VERSION 5.7 ;
  NOWIREEXTENSIONATPIN ON ;
  DIVIDERCHAR "/" ;
  BUSBITCHARS "[]" ;
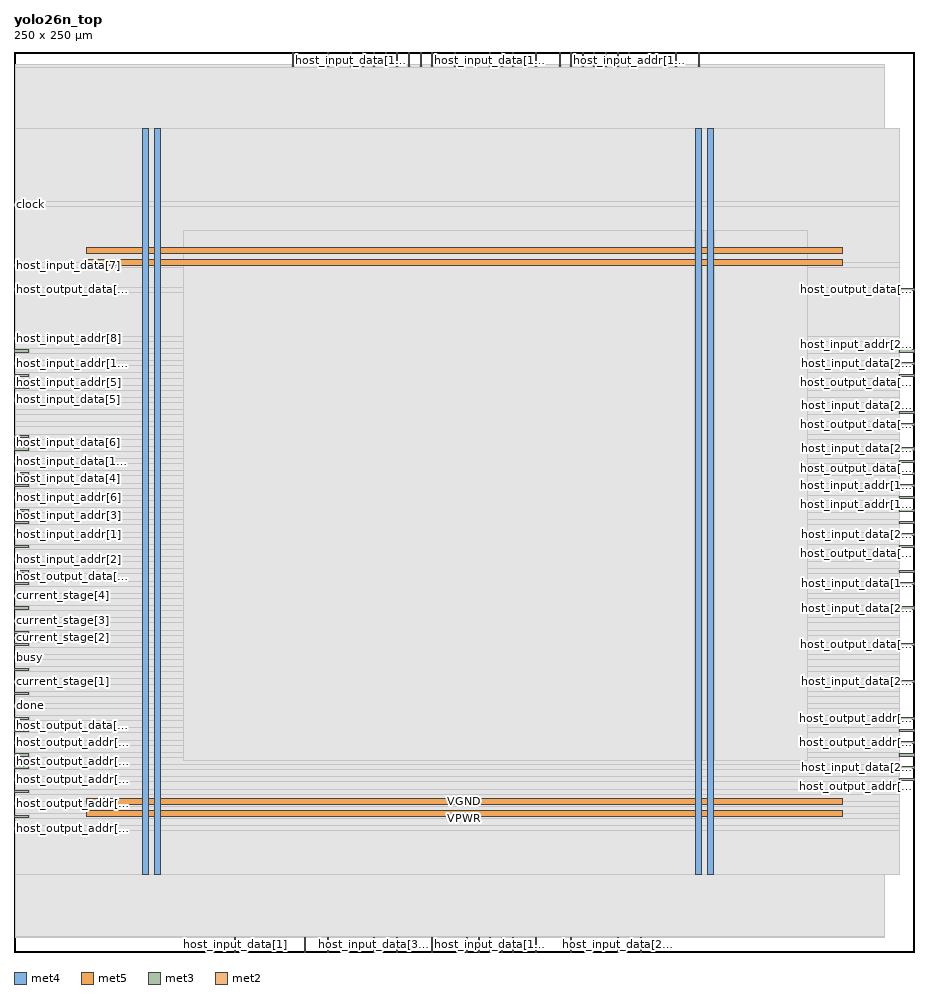
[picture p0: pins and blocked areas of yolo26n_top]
MACRO yolo26n_top
  CLASS BLOCK ;
  FOREIGN yolo26n_top ;
  ORIGIN 0.000 0.000 ;
  SIZE 250.000 BY 250.000 ;
  PIN VGND
    DIRECTION INOUT ;
    USE GROUND ;
    PORT
      LAYER met4 ;
        RECT 39.060 21.520 40.660 228.720 ;
    END
    PORT
      LAYER met4 ;
        RECT 192.660 21.520 194.260 228.720 ;
    END
    PORT
      LAYER met5 ;
        RECT 20.000 40.910 230.240 42.510 ;
    END
    PORT
      LAYER met5 ;
        RECT 20.000 194.090 230.240 195.690 ;
    END
  END VGND
  PIN VPWR
    DIRECTION INOUT ;
    USE POWER ;
    PORT
      LAYER met4 ;
        RECT 35.760 21.520 37.360 228.720 ;
    END
    PORT
      LAYER met4 ;
        RECT 189.360 21.520 190.960 228.720 ;
    END
    PORT
      LAYER met5 ;
        RECT 20.000 37.610 230.240 39.210 ;
    END
    PORT
      LAYER met5 ;
        RECT 20.000 190.790 230.240 192.390 ;
    END
  END VPWR
  PIN busy
    DIRECTION OUTPUT ;
    USE SIGNAL ;
    ANTENNADIFFAREA 0.795200 ;
    PORT
      LAYER met3 ;
        RECT 0.000 81.640 4.000 82.240 ;
    END
  END busy
  PIN clock
    DIRECTION INPUT ;
    USE SIGNAL ;
    ANTENNAGATEAREA 0.852000 ;
    PORT
      LAYER met3 ;
        RECT 0.000 207.440 4.000 208.040 ;
    END
  END clock
  PIN current_stage[0]
    DIRECTION OUTPUT ;
    USE SIGNAL ;
    ANTENNADIFFAREA 0.795200 ;
    PORT
      LAYER met3 ;
        RECT 0.000 71.440 4.000 72.040 ;
    END
  END current_stage[0]
  PIN current_stage[1]
    DIRECTION OUTPUT ;
    USE SIGNAL ;
    ANTENNADIFFAREA 0.795200 ;
    PORT
      LAYER met3 ;
        RECT 0.000 74.840 4.000 75.440 ;
    END
  END current_stage[1]
  PIN current_stage[2]
    DIRECTION OUTPUT ;
    USE SIGNAL ;
    ANTENNADIFFAREA 0.795200 ;
    PORT
      LAYER met3 ;
        RECT 0.000 85.040 4.000 85.640 ;
    END
  END current_stage[2]
  PIN current_stage[3]
    DIRECTION OUTPUT ;
    USE SIGNAL ;
    ANTENNADIFFAREA 0.795200 ;
    PORT
      LAYER met3 ;
        RECT 0.000 91.840 4.000 92.440 ;
    END
  END current_stage[3]
  PIN current_stage[4]
    DIRECTION OUTPUT ;
    USE SIGNAL ;
    ANTENNADIFFAREA 0.795200 ;
    PORT
      LAYER met3 ;
        RECT 0.000 98.640 4.000 99.240 ;
    END
  END current_stage[4]
  PIN done
    DIRECTION OUTPUT ;
    USE SIGNAL ;
    ANTENNADIFFAREA 0.795200 ;
    PORT
      LAYER met3 ;
        RECT 0.000 68.040 4.000 68.640 ;
    END
  END done
  PIN host_input_addr[0]
    DIRECTION INPUT ;
    USE SIGNAL ;
    ANTENNAGATEAREA 0.213000 ;
    PORT
      LAYER met3 ;
        RECT 0.000 112.240 4.000 112.840 ;
    END
  END host_input_addr[0]
  PIN host_input_addr[10]
    DIRECTION INPUT ;
    USE SIGNAL ;
    ANTENNAGATEAREA 0.196500 ;
    PORT
      LAYER met3 ;
        RECT 0.000 163.240 4.000 163.840 ;
    END
  END host_input_addr[10]
  PIN host_input_addr[11]
    DIRECTION INPUT ;
    USE SIGNAL ;
    ANTENNAGATEAREA 0.196500 ;
    PORT
      LAYER met2 ;
        RECT 135.330 246.000 135.610 250.000 ;
    END
  END host_input_addr[11]
  PIN host_input_addr[12]
    DIRECTION INPUT ;
    USE SIGNAL ;
    ANTENNAGATEAREA 0.196500 ;
    PORT
      LAYER met2 ;
        RECT 122.450 246.000 122.730 250.000 ;
    END
  END host_input_addr[12]
  PIN host_input_addr[13]
    DIRECTION INPUT ;
    USE SIGNAL ;
    ANTENNAGATEAREA 0.196500 ;
    PORT
      LAYER met3 ;
        RECT 246.000 122.440 250.000 123.040 ;
    END
  END host_input_addr[13]
  PIN host_input_addr[14]
    DIRECTION INPUT ;
    USE SIGNAL ;
    ANTENNAGATEAREA 0.196500 ;
    PORT
      LAYER met2 ;
        RECT 106.350 246.000 106.630 250.000 ;
    END
  END host_input_addr[14]
  PIN host_input_addr[15]
    DIRECTION INPUT ;
    USE SIGNAL ;
    ANTENNAGATEAREA 0.196500 ;
    PORT
      LAYER met3 ;
        RECT 246.000 129.240 250.000 129.840 ;
    END
  END host_input_addr[15]
  PIN host_input_addr[16]
    DIRECTION INPUT ;
    USE SIGNAL ;
    ANTENNAGATEAREA 0.196500 ;
    PORT
      LAYER met3 ;
        RECT 246.000 132.640 250.000 133.240 ;
    END
  END host_input_addr[16]
  PIN host_input_addr[17]
    DIRECTION INPUT ;
    USE SIGNAL ;
    ANTENNAGATEAREA 0.196500 ;
    PORT
      LAYER met2 ;
        RECT 161.090 246.000 161.370 250.000 ;
    END
  END host_input_addr[17]
  PIN host_input_addr[18]
    DIRECTION INPUT ;
    USE SIGNAL ;
    ANTENNAGATEAREA 0.196500 ;
    PORT
      LAYER met3 ;
        RECT 246.000 125.840 250.000 126.440 ;
    END
  END host_input_addr[18]
  PIN host_input_addr[19]
    DIRECTION INPUT ;
    USE SIGNAL ;
    ANTENNAGATEAREA 0.196500 ;
    PORT
      LAYER met2 ;
        RECT 170.750 246.000 171.030 250.000 ;
    END
  END host_input_addr[19]
  PIN host_input_addr[1]
    DIRECTION INPUT ;
    USE SIGNAL ;
    ANTENNAGATEAREA 0.196500 ;
    PORT
      LAYER met3 ;
        RECT 0.000 115.640 4.000 116.240 ;
    END
  END host_input_addr[1]
  PIN host_input_addr[20]
    DIRECTION INPUT ;
    USE SIGNAL ;
    ANTENNAGATEAREA 0.196500 ;
    PORT
      LAYER met3 ;
        RECT 246.000 166.640 250.000 167.240 ;
    END
  END host_input_addr[20]
  PIN host_input_addr[2]
    DIRECTION INPUT ;
    USE SIGNAL ;
    ANTENNAGATEAREA 0.196500 ;
    PORT
      LAYER met3 ;
        RECT 0.000 108.840 4.000 109.440 ;
    END
  END host_input_addr[2]
  PIN host_input_addr[3]
    DIRECTION INPUT ;
    USE SIGNAL ;
    ANTENNAGATEAREA 0.196500 ;
    PORT
      LAYER met3 ;
        RECT 0.000 119.040 4.000 119.640 ;
    END
  END host_input_addr[3]
  PIN host_input_addr[4]
    DIRECTION INPUT ;
    USE SIGNAL ;
    ANTENNAGATEAREA 0.196500 ;
    PORT
      LAYER met3 ;
        RECT 0.000 122.440 4.000 123.040 ;
    END
  END host_input_addr[4]
  PIN host_input_addr[5]
    DIRECTION INPUT ;
    USE SIGNAL ;
    ANTENNAGATEAREA 0.196500 ;
    PORT
      LAYER met3 ;
        RECT 0.000 159.840 4.000 160.440 ;
    END
  END host_input_addr[5]
  PIN host_input_addr[6]
    DIRECTION INPUT ;
    USE SIGNAL ;
    ANTENNAGATEAREA 0.196500 ;
    PORT
      LAYER met3 ;
        RECT 0.000 125.840 4.000 126.440 ;
    END
  END host_input_addr[6]
  PIN host_input_addr[7]
    DIRECTION INPUT ;
    USE SIGNAL ;
    ANTENNAGATEAREA 0.196500 ;
    PORT
      LAYER met3 ;
        RECT 0.000 166.640 4.000 167.240 ;
    END
  END host_input_addr[7]
  PIN host_input_addr[8]
    DIRECTION INPUT ;
    USE SIGNAL ;
    ANTENNAGATEAREA 0.196500 ;
    PORT
      LAYER met3 ;
        RECT 0.000 170.040 4.000 170.640 ;
    END
  END host_input_addr[8]
  PIN host_input_addr[9]
    DIRECTION INPUT ;
    USE SIGNAL ;
    ANTENNAGATEAREA 0.196500 ;
    PORT
      LAYER met2 ;
        RECT 109.570 246.000 109.850 250.000 ;
    END
  END host_input_addr[9]
  PIN host_input_data[0]
    DIRECTION INPUT ;
    USE SIGNAL ;
    ANTENNAGATEAREA 0.159000 ;
    PORT
      LAYER met2 ;
        RECT 80.590 0.000 80.870 4.000 ;
    END
  END host_input_data[0]
  PIN host_input_data[10]
    DIRECTION INPUT ;
    USE SIGNAL ;
    ANTENNAGATEAREA 0.159000 ;
    PORT
      LAYER met2 ;
        RECT 93.470 246.000 93.750 250.000 ;
    END
  END host_input_data[10]
  PIN host_input_data[11]
    DIRECTION INPUT ;
    USE SIGNAL ;
    ANTENNAGATEAREA 0.159000 ;
    PORT
      LAYER met2 ;
        RECT 151.430 246.000 151.710 250.000 ;
    END
  END host_input_data[11]
  PIN host_input_data[12]
    DIRECTION INPUT ;
    USE SIGNAL ;
    ANTENNAGATEAREA 0.213000 ;
    PORT
      LAYER met2 ;
        RECT 132.110 246.000 132.390 250.000 ;
    END
  END host_input_data[12]
  PIN host_input_data[13]
    DIRECTION INPUT ;
    USE SIGNAL ;
    ANTENNAGATEAREA 0.159000 ;
    PORT
      LAYER met3 ;
        RECT 0.000 136.040 4.000 136.640 ;
    END
  END host_input_data[13]
  PIN host_input_data[14]
    DIRECTION INPUT ;
    USE SIGNAL ;
    ANTENNAGATEAREA 0.159000 ;
    PORT
      LAYER met2 ;
        RECT 99.910 246.000 100.190 250.000 ;
    END
  END host_input_data[14]
  PIN host_input_data[15]
    DIRECTION INPUT ;
    USE SIGNAL ;
    ANTENNAGATEAREA 0.159000 ;
    PORT
      LAYER met2 ;
        RECT 132.110 0.000 132.390 4.000 ;
    END
  END host_input_data[15]
  PIN host_input_data[16]
    DIRECTION INPUT ;
    USE SIGNAL ;
    ANTENNAGATEAREA 0.159000 ;
    PORT
      LAYER met2 ;
        RECT 154.650 246.000 154.930 250.000 ;
    END
  END host_input_data[16]
  PIN host_input_data[17]
    DIRECTION INPUT ;
    USE SIGNAL ;
    ANTENNAGATEAREA 0.213000 ;
    PORT
      LAYER met2 ;
        RECT 157.870 246.000 158.150 250.000 ;
    END
  END host_input_data[17]
  PIN host_input_data[18]
    DIRECTION INPUT ;
    USE SIGNAL ;
    ANTENNAGATEAREA 0.213000 ;
    PORT
      LAYER met3 ;
        RECT 246.000 102.040 250.000 102.640 ;
    END
  END host_input_data[18]
  PIN host_input_data[19]
    DIRECTION INPUT ;
    USE SIGNAL ;
    ANTENNAGATEAREA 0.159000 ;
    PORT
      LAYER met2 ;
        RECT 190.070 246.000 190.350 250.000 ;
    END
  END host_input_data[19]
  PIN host_input_data[1]
    DIRECTION INPUT ;
    USE SIGNAL ;
    ANTENNAGATEAREA 0.159000 ;
    PORT
      LAYER met2 ;
        RECT 61.270 0.000 61.550 4.000 ;
    END
  END host_input_data[1]
  PIN host_input_data[20]
    DIRECTION INPUT ;
    USE SIGNAL ;
    ANTENNAGATEAREA 0.159000 ;
    PORT
      LAYER met3 ;
        RECT 246.000 163.240 250.000 163.840 ;
    END
  END host_input_data[20]
  PIN host_input_data[21]
    DIRECTION INPUT ;
    USE SIGNAL ;
    ANTENNAGATEAREA 0.213000 ;
    PORT
      LAYER met3 ;
        RECT 246.000 149.640 250.000 150.240 ;
    END
  END host_input_data[21]
  PIN host_input_data[22]
    DIRECTION INPUT ;
    USE SIGNAL ;
    ANTENNAGATEAREA 0.159000 ;
    PORT
      LAYER met3 ;
        RECT 246.000 115.640 250.000 116.240 ;
    END
  END host_input_data[22]
  PIN host_input_data[23]
    DIRECTION INPUT ;
    USE SIGNAL ;
    ANTENNAGATEAREA 0.213000 ;
    PORT
      LAYER met3 ;
        RECT 246.000 139.440 250.000 140.040 ;
    END
  END host_input_data[23]
  PIN host_input_data[24]
    DIRECTION INPUT ;
    USE SIGNAL ;
    ANTENNAGATEAREA 0.213000 ;
    PORT
      LAYER met2 ;
        RECT 167.530 0.000 167.810 4.000 ;
    END
  END host_input_data[24]
  PIN host_input_data[25]
    DIRECTION INPUT ;
    USE SIGNAL ;
    ANTENNAGATEAREA 0.159000 ;
    PORT
      LAYER met3 ;
        RECT 246.000 51.040 250.000 51.640 ;
    END
  END host_input_data[25]
  PIN host_input_data[26]
    DIRECTION INPUT ;
    USE SIGNAL ;
    ANTENNAGATEAREA 0.213000 ;
    PORT
      LAYER met3 ;
        RECT 246.000 74.840 250.000 75.440 ;
    END
  END host_input_data[26]
  PIN host_input_data[27]
    DIRECTION INPUT ;
    USE SIGNAL ;
    ANTENNAGATEAREA 0.213000 ;
    PORT
      LAYER met3 ;
        RECT 246.000 95.240 250.000 95.840 ;
    END
  END host_input_data[27]
  PIN host_input_data[28]
    DIRECTION INPUT ;
    USE SIGNAL ;
    ANTENNAGATEAREA 0.159000 ;
    PORT
      LAYER met2 ;
        RECT 144.990 0.000 145.270 4.000 ;
    END
  END host_input_data[28]
  PIN host_input_data[29]
    DIRECTION INPUT ;
    USE SIGNAL ;
    ANTENNAGATEAREA 0.159000 ;
    PORT
      LAYER met2 ;
        RECT 135.330 0.000 135.610 4.000 ;
    END
  END host_input_data[29]
  PIN host_input_data[2]
    DIRECTION INPUT ;
    USE SIGNAL ;
    ANTENNAGATEAREA 0.159000 ;
    PORT
      LAYER met3 ;
        RECT 0.000 78.240 4.000 78.840 ;
    END
  END host_input_data[2]
  PIN host_input_data[30]
    DIRECTION INPUT ;
    USE SIGNAL ;
    ANTENNAGATEAREA 0.159000 ;
    PORT
      LAYER met2 ;
        RECT 116.010 0.000 116.290 4.000 ;
    END
  END host_input_data[30]
  PIN host_input_data[31]
    DIRECTION INPUT ;
    USE SIGNAL ;
    ANTENNAGATEAREA 0.159000 ;
    PORT
      LAYER met2 ;
        RECT 99.910 0.000 100.190 4.000 ;
    END
  END host_input_data[31]
  PIN host_input_data[3]
    DIRECTION INPUT ;
    USE SIGNAL ;
    ANTENNAGATEAREA 0.159000 ;
    PORT
      LAYER met2 ;
        RECT 87.030 0.000 87.310 4.000 ;
    END
  END host_input_data[3]
  PIN host_input_data[4]
    DIRECTION INPUT ;
    USE SIGNAL ;
    ANTENNAGATEAREA 0.159000 ;
    PORT
      LAYER met3 ;
        RECT 0.000 129.240 4.000 129.840 ;
    END
  END host_input_data[4]
  PIN host_input_data[5]
    DIRECTION INPUT ;
    USE SIGNAL ;
    ANTENNAGATEAREA 0.213000 ;
    PORT
      LAYER met3 ;
        RECT 0.000 153.040 4.000 153.640 ;
    END
  END host_input_data[5]
  PIN host_input_data[6]
    DIRECTION INPUT ;
    USE SIGNAL ;
    ANTENNAGATEAREA 0.213000 ;
    PORT
      LAYER met3 ;
        RECT 0.000 139.440 4.000 140.040 ;
    END
  END host_input_data[6]
  PIN host_input_data[7]
    DIRECTION INPUT ;
    USE SIGNAL ;
    ANTENNAGATEAREA 0.159000 ;
    PORT
      LAYER met3 ;
        RECT 0.000 190.440 4.000 191.040 ;
    END
  END host_input_data[7]
  PIN host_input_data[8]
    DIRECTION INPUT ;
    USE SIGNAL ;
    ANTENNAGATEAREA 0.159000 ;
    PORT
      LAYER met2 ;
        RECT 87.030 246.000 87.310 250.000 ;
    END
  END host_input_data[8]
  PIN host_input_data[9]
    DIRECTION INPUT ;
    USE SIGNAL ;
    ANTENNAGATEAREA 0.213000 ;
    PORT
      LAYER met2 ;
        RECT 112.790 246.000 113.070 250.000 ;
    END
  END host_input_data[9]
  PIN host_input_we
    DIRECTION INPUT ;
    USE SIGNAL ;
    ANTENNAGATEAREA 0.196500 ;
    PORT
      LAYER met2 ;
        RECT 164.310 246.000 164.590 250.000 ;
    END
  END host_input_we
  PIN host_output_addr[0]
    DIRECTION INPUT ;
    USE SIGNAL ;
    ANTENNAGATEAREA 0.196500 ;
    PORT
      LAYER met3 ;
        RECT 246.000 47.640 250.000 48.240 ;
    END
  END host_output_addr[0]
  PIN host_output_addr[10]
    DIRECTION INPUT ;
    USE SIGNAL ;
    ANTENNAGATEAREA 0.196500 ;
    PORT
      LAYER met3 ;
        RECT 0.000 54.440 4.000 55.040 ;
    END
  END host_output_addr[10]
  PIN host_output_addr[1]
    DIRECTION INPUT ;
    USE SIGNAL ;
    ANTENNAGATEAREA 0.196500 ;
    PORT
      LAYER met3 ;
        RECT 246.000 64.640 250.000 65.240 ;
    END
  END host_output_addr[1]
  PIN host_output_addr[2]
    DIRECTION INPUT ;
    USE SIGNAL ;
    ANTENNAGATEAREA 0.196500 ;
    PORT
      LAYER met3 ;
        RECT 246.000 57.840 250.000 58.440 ;
    END
  END host_output_addr[2]
  PIN host_output_addr[3]
    DIRECTION INPUT ;
    USE SIGNAL ;
    ANTENNAGATEAREA 0.196500 ;
    PORT
      LAYER met3 ;
        RECT 0.000 57.840 4.000 58.440 ;
    END
  END host_output_addr[3]
  PIN host_output_addr[4]
    DIRECTION INPUT ;
    USE SIGNAL ;
    ANTENNAGATEAREA 0.196500 ;
    PORT
      LAYER met3 ;
        RECT 0.000 34.040 4.000 34.640 ;
    END
  END host_output_addr[4]
  PIN host_output_addr[5]
    DIRECTION INPUT ;
    USE SIGNAL ;
    ANTENNAGATEAREA 0.196500 ;
    PORT
      LAYER met3 ;
        RECT 0.000 47.640 4.000 48.240 ;
    END
  END host_output_addr[5]
  PIN host_output_addr[6]
    DIRECTION INPUT ;
    USE SIGNAL ;
    ANTENNAGATEAREA 0.196500 ;
    PORT
      LAYER met3 ;
        RECT 0.000 51.040 4.000 51.640 ;
    END
  END host_output_addr[6]
  PIN host_output_addr[7]
    DIRECTION INPUT ;
    USE SIGNAL ;
    ANTENNAGATEAREA 0.196500 ;
    PORT
      LAYER met3 ;
        RECT 0.000 37.440 4.000 38.040 ;
    END
  END host_output_addr[7]
  PIN host_output_addr[8]
    DIRECTION INPUT ;
    USE SIGNAL ;
    ANTENNAGATEAREA 0.196500 ;
    PORT
      LAYER met3 ;
        RECT 0.000 44.240 4.000 44.840 ;
    END
  END host_output_addr[8]
  PIN host_output_addr[9]
    DIRECTION INPUT ;
    USE SIGNAL ;
    ANTENNAGATEAREA 0.196500 ;
    PORT
      LAYER met3 ;
        RECT 0.000 40.840 4.000 41.440 ;
    END
  END host_output_addr[9]
  PIN host_output_data[0]
    DIRECTION OUTPUT ;
    USE SIGNAL ;
    ANTENNADIFFAREA 0.795200 ;
    PORT
      LAYER met3 ;
        RECT 0.000 64.640 4.000 65.240 ;
    END
  END host_output_data[0]
  PIN host_output_data[10]
    DIRECTION OUTPUT ;
    USE SIGNAL ;
    ANTENNADIFFAREA 0.445500 ;
    PORT
      LAYER met2 ;
        RECT 96.690 246.000 96.970 250.000 ;
    END
  END host_output_data[10]
  PIN host_output_data[11]
    DIRECTION OUTPUT ;
    USE SIGNAL ;
    ANTENNADIFFAREA 0.445500 ;
    PORT
      LAYER met2 ;
        RECT 144.990 246.000 145.270 250.000 ;
    END
  END host_output_data[11]
  PIN host_output_data[12]
    DIRECTION OUTPUT ;
    USE SIGNAL ;
    ANTENNADIFFAREA 0.445500 ;
    PORT
      LAYER met2 ;
        RECT 138.550 246.000 138.830 250.000 ;
    END
  END host_output_data[12]
  PIN host_output_data[13]
    DIRECTION OUTPUT ;
    USE SIGNAL ;
    ANTENNADIFFAREA 0.795200 ;
    PORT
      LAYER met3 ;
        RECT 0.000 132.640 4.000 133.240 ;
    END
  END host_output_data[13]
  PIN host_output_data[14]
    DIRECTION OUTPUT ;
    USE SIGNAL ;
    ANTENNADIFFAREA 0.445500 ;
    PORT
      LAYER met2 ;
        RECT 103.130 246.000 103.410 250.000 ;
    END
  END host_output_data[14]
  PIN host_output_data[15]
    DIRECTION OUTPUT ;
    USE SIGNAL ;
    ANTENNADIFFAREA 0.445500 ;
    PORT
      LAYER met2 ;
        RECT 128.890 0.000 129.170 4.000 ;
    END
  END host_output_data[15]
  PIN host_output_data[16]
    DIRECTION OUTPUT ;
    USE SIGNAL ;
    ANTENNADIFFAREA 0.445500 ;
    PORT
      LAYER met3 ;
        RECT 246.000 146.240 250.000 146.840 ;
    END
  END host_output_data[16]
  PIN host_output_data[17]
    DIRECTION OUTPUT ;
    USE SIGNAL ;
    ANTENNADIFFAREA 0.445500 ;
    PORT
      LAYER met2 ;
        RECT 167.530 246.000 167.810 250.000 ;
    END
  END host_output_data[17]
  PIN host_output_data[18]
    DIRECTION OUTPUT ;
    USE SIGNAL ;
    ANTENNADIFFAREA 0.445500 ;
    PORT
      LAYER met3 ;
        RECT 246.000 112.240 250.000 112.840 ;
    END
  END host_output_data[18]
  PIN host_output_data[19]
    DIRECTION OUTPUT ;
    USE SIGNAL ;
    ANTENNADIFFAREA 0.445500 ;
    PORT
      LAYER met2 ;
        RECT 183.630 246.000 183.910 250.000 ;
    END
  END host_output_data[19]
  PIN host_output_data[1]
    DIRECTION OUTPUT ;
    USE SIGNAL ;
    ANTENNADIFFAREA 0.795200 ;
    PORT
      LAYER met3 ;
        RECT 0.000 61.240 4.000 61.840 ;
    END
  END host_output_data[1]
  PIN host_output_data[20]
    DIRECTION OUTPUT ;
    USE SIGNAL ;
    ANTENNADIFFAREA 0.445500 ;
    PORT
      LAYER met3 ;
        RECT 246.000 183.640 250.000 184.240 ;
    END
  END host_output_data[20]
  PIN host_output_data[21]
    DIRECTION OUTPUT ;
    USE SIGNAL ;
    ANTENNADIFFAREA 0.445500 ;
    PORT
      LAYER met3 ;
        RECT 246.000 159.840 250.000 160.440 ;
    END
  END host_output_data[21]
  PIN host_output_data[22]
    DIRECTION OUTPUT ;
    USE SIGNAL ;
    ANTENNADIFFAREA 0.445500 ;
    PORT
      LAYER met3 ;
        RECT 246.000 119.040 250.000 119.640 ;
    END
  END host_output_data[22]
  PIN host_output_data[23]
    DIRECTION OUTPUT ;
    USE SIGNAL ;
    ANTENNADIFFAREA 0.445500 ;
    PORT
      LAYER met3 ;
        RECT 246.000 136.040 250.000 136.640 ;
    END
  END host_output_data[23]
  PIN host_output_data[24]
    DIRECTION OUTPUT ;
    USE SIGNAL ;
    ANTENNADIFFAREA 0.445500 ;
    PORT
      LAYER met2 ;
        RECT 173.970 0.000 174.250 4.000 ;
    END
  END host_output_data[24]
  PIN host_output_data[25]
    DIRECTION OUTPUT ;
    USE SIGNAL ;
    ANTENNADIFFAREA 0.445500 ;
    PORT
      LAYER met3 ;
        RECT 246.000 61.240 250.000 61.840 ;
    END
  END host_output_data[25]
  PIN host_output_data[26]
    DIRECTION OUTPUT ;
    USE SIGNAL ;
    ANTENNADIFFAREA 0.445500 ;
    PORT
      LAYER met3 ;
        RECT 246.000 85.040 250.000 85.640 ;
    END
  END host_output_data[26]
  PIN host_output_data[27]
    DIRECTION OUTPUT ;
    USE SIGNAL ;
    ANTENNADIFFAREA 0.445500 ;
    PORT
      LAYER met3 ;
        RECT 246.000 105.440 250.000 106.040 ;
    END
  END host_output_data[27]
  PIN host_output_data[28]
    DIRECTION OUTPUT ;
    USE SIGNAL ;
    ANTENNADIFFAREA 0.445500 ;
    PORT
      LAYER met2 ;
        RECT 154.650 0.000 154.930 4.000 ;
    END
  END host_output_data[28]
  PIN host_output_data[29]
    DIRECTION OUTPUT ;
    USE SIGNAL ;
    ANTENNADIFFAREA 0.445500 ;
    PORT
      LAYER met2 ;
        RECT 138.550 0.000 138.830 4.000 ;
    END
  END host_output_data[29]
  PIN host_output_data[2]
    DIRECTION OUTPUT ;
    USE SIGNAL ;
    ANTENNADIFFAREA 0.795200 ;
    PORT
      LAYER met3 ;
        RECT 0.000 88.440 4.000 89.040 ;
    END
  END host_output_data[2]
  PIN host_output_data[30]
    DIRECTION OUTPUT ;
    USE SIGNAL ;
    ANTENNADIFFAREA 0.445500 ;
    PORT
      LAYER met2 ;
        RECT 125.670 0.000 125.950 4.000 ;
    END
  END host_output_data[30]
  PIN host_output_data[31]
    DIRECTION OUTPUT ;
    USE SIGNAL ;
    ANTENNADIFFAREA 0.445500 ;
    PORT
      LAYER met2 ;
        RECT 106.350 0.000 106.630 4.000 ;
    END
  END host_output_data[31]
  PIN host_output_data[3]
    DIRECTION OUTPUT ;
    USE SIGNAL ;
    ANTENNADIFFAREA 0.795200 ;
    PORT
      LAYER met3 ;
        RECT 0.000 95.240 4.000 95.840 ;
    END
  END host_output_data[3]
  PIN host_output_data[4]
    DIRECTION OUTPUT ;
    USE SIGNAL ;
    ANTENNADIFFAREA 0.795200 ;
    PORT
      LAYER met3 ;
        RECT 0.000 102.040 4.000 102.640 ;
    END
  END host_output_data[4]
  PIN host_output_data[5]
    DIRECTION OUTPUT ;
    USE SIGNAL ;
    ANTENNADIFFAREA 0.795200 ;
    PORT
      LAYER met3 ;
        RECT 0.000 156.440 4.000 157.040 ;
    END
  END host_output_data[5]
  PIN host_output_data[6]
    DIRECTION OUTPUT ;
    USE SIGNAL ;
    ANTENNADIFFAREA 0.795200 ;
    PORT
      LAYER met3 ;
        RECT 0.000 142.840 4.000 143.440 ;
    END
  END host_output_data[6]
  PIN host_output_data[7]
    DIRECTION OUTPUT ;
    USE SIGNAL ;
    ANTENNADIFFAREA 0.795200 ;
    PORT
      LAYER met3 ;
        RECT 0.000 183.640 4.000 184.240 ;
    END
  END host_output_data[7]
  PIN host_output_data[8]
    DIRECTION OUTPUT ;
    USE SIGNAL ;
    ANTENNADIFFAREA 0.445500 ;
    PORT
      LAYER met2 ;
        RECT 77.370 246.000 77.650 250.000 ;
    END
  END host_output_data[8]
  PIN host_output_data[9]
    DIRECTION OUTPUT ;
    USE SIGNAL ;
    ANTENNADIFFAREA 0.445500 ;
    PORT
      LAYER met2 ;
        RECT 116.010 246.000 116.290 250.000 ;
    END
  END host_output_data[9]
  PIN reset
    DIRECTION INPUT ;
    USE SIGNAL ;
    ANTENNAGATEAREA 0.196500 ;
    PORT
      LAYER met3 ;
        RECT 246.000 54.440 250.000 55.040 ;
    END
  END reset
  PIN start
    DIRECTION INPUT ;
    USE SIGNAL ;
    ANTENNAGATEAREA 0.196500 ;
    PORT
      LAYER met3 ;
        RECT 0.000 105.440 4.000 106.040 ;
    END
  END start
  OBS
      LAYER nwell ;
        RECT 20.050 21.675 230.190 228.565 ;
      LAYER li1 ;
        RECT 20.240 21.675 230.000 228.565 ;
      LAYER met1 ;
        RECT 6.050 21.520 241.890 228.720 ;
      LAYER met2 ;
        RECT 0.550 245.720 77.090 246.570 ;
        RECT 77.930 245.720 86.750 246.570 ;
        RECT 87.590 245.720 93.190 246.570 ;
        RECT 94.030 245.720 96.410 246.570 ;
        RECT 97.250 245.720 99.630 246.570 ;
        RECT 100.470 245.720 102.850 246.570 ;
        RECT 103.690 245.720 106.070 246.570 ;
        RECT 106.910 245.720 109.290 246.570 ;
        RECT 110.130 245.720 112.510 246.570 ;
        RECT 113.350 245.720 115.730 246.570 ;
        RECT 116.570 245.720 122.170 246.570 ;
        RECT 123.010 245.720 131.830 246.570 ;
        RECT 132.670 245.720 135.050 246.570 ;
        RECT 135.890 245.720 138.270 246.570 ;
        RECT 139.110 245.720 144.710 246.570 ;
        RECT 145.550 245.720 151.150 246.570 ;
        RECT 151.990 245.720 154.370 246.570 ;
        RECT 155.210 245.720 157.590 246.570 ;
        RECT 158.430 245.720 160.810 246.570 ;
        RECT 161.650 245.720 164.030 246.570 ;
        RECT 164.870 245.720 167.250 246.570 ;
        RECT 168.090 245.720 170.470 246.570 ;
        RECT 171.310 245.720 183.350 246.570 ;
        RECT 184.190 245.720 189.790 246.570 ;
        RECT 190.630 245.720 241.870 246.570 ;
        RECT 0.550 4.280 241.870 245.720 ;
        RECT 0.550 4.000 60.990 4.280 ;
        RECT 61.830 4.000 80.310 4.280 ;
        RECT 81.150 4.000 86.750 4.280 ;
        RECT 87.590 4.000 99.630 4.280 ;
        RECT 100.470 4.000 106.070 4.280 ;
        RECT 106.910 4.000 115.730 4.280 ;
        RECT 116.570 4.000 125.390 4.280 ;
        RECT 126.230 4.000 128.610 4.280 ;
        RECT 129.450 4.000 131.830 4.280 ;
        RECT 132.670 4.000 135.050 4.280 ;
        RECT 135.890 4.000 138.270 4.280 ;
        RECT 139.110 4.000 144.710 4.280 ;
        RECT 145.550 4.000 154.370 4.280 ;
        RECT 155.210 4.000 167.250 4.280 ;
        RECT 168.090 4.000 173.690 4.280 ;
        RECT 174.530 4.000 241.870 4.280 ;
      LAYER met3 ;
        RECT 0.525 208.440 246.000 228.645 ;
        RECT 4.400 207.040 246.000 208.440 ;
        RECT 0.525 191.440 246.000 207.040 ;
        RECT 4.400 190.040 246.000 191.440 ;
        RECT 0.525 184.640 246.000 190.040 ;
        RECT 4.400 183.240 245.600 184.640 ;
        RECT 0.525 171.040 246.000 183.240 ;
        RECT 4.400 169.640 246.000 171.040 ;
        RECT 0.525 167.640 246.000 169.640 ;
        RECT 4.400 166.240 245.600 167.640 ;
        RECT 0.525 164.240 246.000 166.240 ;
        RECT 4.400 162.840 245.600 164.240 ;
        RECT 0.525 160.840 246.000 162.840 ;
        RECT 4.400 159.440 245.600 160.840 ;
        RECT 0.525 157.440 246.000 159.440 ;
        RECT 4.400 156.040 246.000 157.440 ;
        RECT 0.525 154.040 246.000 156.040 ;
        RECT 4.400 152.640 246.000 154.040 ;
        RECT 0.525 150.640 246.000 152.640 ;
        RECT 0.525 149.240 245.600 150.640 ;
        RECT 0.525 147.240 246.000 149.240 ;
        RECT 0.525 145.840 245.600 147.240 ;
        RECT 0.525 143.840 246.000 145.840 ;
        RECT 4.400 142.440 246.000 143.840 ;
        RECT 0.525 140.440 246.000 142.440 ;
        RECT 4.400 139.040 245.600 140.440 ;
        RECT 0.525 137.040 246.000 139.040 ;
        RECT 4.400 135.640 245.600 137.040 ;
        RECT 0.525 133.640 246.000 135.640 ;
        RECT 4.400 132.240 245.600 133.640 ;
        RECT 0.525 130.240 246.000 132.240 ;
        RECT 4.400 128.840 245.600 130.240 ;
        RECT 0.525 126.840 246.000 128.840 ;
        RECT 4.400 125.440 245.600 126.840 ;
        RECT 0.525 123.440 246.000 125.440 ;
        RECT 4.400 122.040 245.600 123.440 ;
        RECT 0.525 120.040 246.000 122.040 ;
        RECT 4.400 118.640 245.600 120.040 ;
        RECT 0.525 116.640 246.000 118.640 ;
        RECT 4.400 115.240 245.600 116.640 ;
        RECT 0.525 113.240 246.000 115.240 ;
        RECT 4.400 111.840 245.600 113.240 ;
        RECT 0.525 109.840 246.000 111.840 ;
        RECT 4.400 108.440 246.000 109.840 ;
        RECT 0.525 106.440 246.000 108.440 ;
        RECT 4.400 105.040 245.600 106.440 ;
        RECT 0.525 103.040 246.000 105.040 ;
        RECT 4.400 101.640 245.600 103.040 ;
        RECT 0.525 99.640 246.000 101.640 ;
        RECT 4.400 98.240 246.000 99.640 ;
        RECT 0.525 96.240 246.000 98.240 ;
        RECT 4.400 94.840 245.600 96.240 ;
        RECT 0.525 92.840 246.000 94.840 ;
        RECT 4.400 91.440 246.000 92.840 ;
        RECT 0.525 89.440 246.000 91.440 ;
        RECT 4.400 88.040 246.000 89.440 ;
        RECT 0.525 86.040 246.000 88.040 ;
        RECT 4.400 84.640 245.600 86.040 ;
        RECT 0.525 82.640 246.000 84.640 ;
        RECT 4.400 81.240 246.000 82.640 ;
        RECT 0.525 79.240 246.000 81.240 ;
        RECT 4.400 77.840 246.000 79.240 ;
        RECT 0.525 75.840 246.000 77.840 ;
        RECT 4.400 74.440 245.600 75.840 ;
        RECT 0.525 72.440 246.000 74.440 ;
        RECT 4.400 71.040 246.000 72.440 ;
        RECT 0.525 69.040 246.000 71.040 ;
        RECT 4.400 67.640 246.000 69.040 ;
        RECT 0.525 65.640 246.000 67.640 ;
        RECT 4.400 64.240 245.600 65.640 ;
        RECT 0.525 62.240 246.000 64.240 ;
        RECT 4.400 60.840 245.600 62.240 ;
        RECT 0.525 58.840 246.000 60.840 ;
        RECT 4.400 57.440 245.600 58.840 ;
        RECT 0.525 55.440 246.000 57.440 ;
        RECT 4.400 54.040 245.600 55.440 ;
        RECT 0.525 52.040 246.000 54.040 ;
        RECT 4.400 50.640 245.600 52.040 ;
        RECT 0.525 48.640 246.000 50.640 ;
        RECT 4.400 47.240 245.600 48.640 ;
        RECT 0.525 45.240 246.000 47.240 ;
        RECT 4.400 43.840 246.000 45.240 ;
        RECT 0.525 41.840 246.000 43.840 ;
        RECT 4.400 40.440 246.000 41.840 ;
        RECT 0.525 38.440 246.000 40.440 ;
        RECT 4.400 37.040 246.000 38.440 ;
        RECT 0.525 35.040 246.000 37.040 ;
        RECT 4.400 33.640 246.000 35.040 ;
        RECT 0.525 21.595 246.000 33.640 ;
      LAYER met4 ;
        RECT 47.215 53.215 188.960 200.425 ;
        RECT 191.360 53.215 192.260 200.425 ;
        RECT 194.660 53.215 220.505 200.425 ;
  END
END yolo26n_top
END LIBRARY

